###############################################################
#  Generated by:      Cadence Innovus 20.13-s083_1
#  OS:                Linux x86_64(Host ID caddy11)
#  Generated on:      Wed Jun 16 17:47:28 2021
#  Design:            deconv_kernel_estimator_top_level
#  Command:           write_lef_abstract -specifyTopLayer 6 -PGPinLayers {5 6} -noCutObs -stripePin results/deconv_kernel_estimator_top_level.lef
###############################################################

VERSION 5.8 ;

BUSBITCHARS "[]" ;
DIVIDERCHAR "/" ;

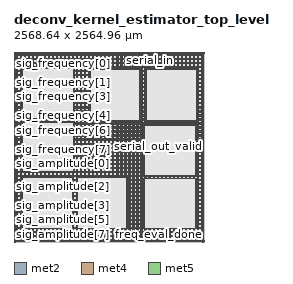
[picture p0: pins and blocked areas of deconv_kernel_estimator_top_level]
MACRO deconv_kernel_estimator_top_level
  CLASS BLOCK ;
  SIZE 2568.640000 BY 2564.960000 ;
  FOREIGN deconv_kernel_estimator_top_level 0.000000 0.000000 ;
  ORIGIN 0 0 ;
  SYMMETRY X Y R90 ;
  PIN clk
    DIRECTION INPUT ;
    USE SIGNAL ;
    ANTENNAPARTIALMETALAREA 5.369 LAYER met2  ;
    ANTENNAPARTIALMETALSIDEAREA 26.684 LAYER met2  ;
    ANTENNAPARTIALCUTAREA 0.04 LAYER via2  ;
    ANTENNAPARTIALMETALAREA 16.5408 LAYER met3  ;
    ANTENNAPARTIALMETALSIDEAREA 88.688 LAYER met3  ;
    ANTENNAMODEL OXIDE1 ;
    ANTENNAGATEAREA 1.152 LAYER met3  ;
    ANTENNAMAXAREACAR 14.9877 LAYER met3  ;
    ANTENNAMAXSIDEAREACAR 78.3273 LAYER met3  ;
    ANTENNAMAXCUTCAR 0.0793403 LAYER via3  ;
    PORT
      LAYER met2 ;
        RECT 1.080000 2564.475000 1.220000 2564.960000 ;
    END
  END clk
  PIN rst_n
    DIRECTION INPUT ;
    USE SIGNAL ;
    ANTENNAPARTIALMETALAREA 18.8185 LAYER met2  ;
    ANTENNAPARTIALMETALSIDEAREA 93.8665 LAYER met2  ;
    ANTENNAMODEL OXIDE1 ;
    ANTENNAGATEAREA 1.33 LAYER met2  ;
    ANTENNAMAXAREACAR 24.5465 LAYER met2  ;
    ANTENNAMAXSIDEAREACAR 121.902 LAYER met2  ;
    ANTENNAMAXCUTCAR 0.0386466 LAYER via2  ;
    PORT
      LAYER met2 ;
        RECT 366.780000 2564.475000 366.920000 2564.960000 ;
    END
  END rst_n
  PIN load_en
    DIRECTION INPUT ;
    USE SIGNAL ;
    ANTENNAPARTIALMETALAREA 125.297 LAYER met2  ;
    ANTENNAPARTIALMETALSIDEAREA 626.206 LAYER met2  ;
    ANTENNAPARTIALCUTAREA 0.04 LAYER via2  ;
    ANTENNAPARTIALMETALAREA 0.255 LAYER met3  ;
    ANTENNAPARTIALMETALSIDEAREA 1.808 LAYER met3  ;
    ANTENNAPARTIALCUTAREA 0.04 LAYER via3  ;
    ANTENNAPARTIALMETALAREA 4.3278 LAYER met4  ;
    ANTENNAPARTIALMETALSIDEAREA 23.552 LAYER met4  ;
    ANTENNAMODEL OXIDE1 ;
    ANTENNAGATEAREA 0.1965 LAYER met4  ;
    ANTENNAMAXAREACAR 29.8453 LAYER met4  ;
    ANTENNAMAXSIDEAREACAR 153.252 LAYER met4  ;
    ANTENNAMAXCUTCAR 0.668702 LAYER via4  ;
    PORT
      LAYER met2 ;
        RECT 733.860000 2564.475000 734.000000 2564.960000 ;
    END
  END load_en
  PIN debug_en
    DIRECTION INPUT ;
    USE SIGNAL ;
    ANTENNAPARTIALMETALAREA 57.8772 LAYER met2  ;
    ANTENNAPARTIALMETALSIDEAREA 289.107 LAYER met2  ;
    ANTENNAPARTIALCUTAREA 0.04 LAYER via2  ;
    ANTENNAPARTIALMETALAREA 11.026 LAYER met3  ;
    ANTENNAPARTIALMETALSIDEAREA 59.272 LAYER met3  ;
    ANTENNAPARTIALCUTAREA 0.04 LAYER via3  ;
    ANTENNAPARTIALMETALAREA 30.9108 LAYER met4  ;
    ANTENNAPARTIALMETALSIDEAREA 165.328 LAYER met4  ;
    ANTENNAMODEL OXIDE1 ;
    ANTENNAGATEAREA 0.441 LAYER met4  ;
    ANTENNAMAXAREACAR 77.8586 LAYER met4  ;
    ANTENNAMAXSIDEAREACAR 407.197 LAYER met4  ;
    ANTENNAMAXCUTCAR 0.589342 LAYER via4  ;
    PORT
      LAYER met2 ;
        RECT 1100.480000 2564.475000 1100.620000 2564.960000 ;
    END
  END debug_en
  PIN serial_in
    DIRECTION INPUT ;
    USE SIGNAL ;
    ANTENNAPARTIALMETALAREA 71.4194 LAYER met2  ;
    ANTENNAPARTIALMETALSIDEAREA 356.818 LAYER met2  ;
    ANTENNAPARTIALCUTAREA 0.04 LAYER via2  ;
    ANTENNAPARTIALMETALAREA 0.2509 LAYER met3  ;
    ANTENNAPARTIALMETALSIDEAREA 1.808 LAYER met3  ;
    ANTENNAPARTIALCUTAREA 0.04 LAYER via3  ;
    ANTENNAPARTIALMETALAREA 3.9618 LAYER met4  ;
    ANTENNAPARTIALMETALSIDEAREA 21.6 LAYER met4  ;
    ANTENNAMODEL OXIDE1 ;
    ANTENNAGATEAREA 0.1965 LAYER met4  ;
    ANTENNAMAXAREACAR 71.0814 LAYER met4  ;
    ANTENNAMAXSIDEAREACAR 363.679 LAYER met4  ;
    ANTENNAMAXCUTCAR 0.668702 LAYER via4  ;
    PORT
      LAYER met2 ;
        RECT 1834.180000 2564.475000 1834.320000 2564.960000 ;
    END
  END serial_in
  PIN sram_select[1]
    DIRECTION INPUT ;
    USE SIGNAL ;
    ANTENNAPARTIALMETALAREA 159.296 LAYER met2  ;
    ANTENNAPARTIALMETALSIDEAREA 796.201 LAYER met2  ;
    ANTENNAPARTIALCUTAREA 0.04 LAYER via2  ;
    ANTENNAPARTIALMETALAREA 0.2509 LAYER met3  ;
    ANTENNAPARTIALMETALSIDEAREA 1.808 LAYER met3  ;
    ANTENNAPARTIALCUTAREA 0.04 LAYER via3  ;
    ANTENNAPARTIALMETALAREA 4.1448 LAYER met4  ;
    ANTENNAPARTIALMETALSIDEAREA 22.576 LAYER met4  ;
    ANTENNAMODEL OXIDE1 ;
    ANTENNAGATEAREA 1.33 LAYER met4  ;
    ANTENNAMAXAREACAR 7.30962 LAYER met4  ;
    ANTENNAMAXSIDEAREACAR 37.5669 LAYER met4  ;
    ANTENNAMAXCUTCAR 0.098797 LAYER via4  ;
    PORT
      LAYER met2 ;
        RECT 2567.420000 2564.475000 2567.560000 2564.960000 ;
    END
  END sram_select[1]
  PIN sram_select[0]
    DIRECTION INPUT ;
    USE SIGNAL ;
    ANTENNAPARTIALMETALAREA 90.3334 LAYER met2  ;
    ANTENNAPARTIALMETALSIDEAREA 451.388 LAYER met2  ;
    ANTENNAPARTIALCUTAREA 0.04 LAYER via2  ;
    ANTENNAPARTIALMETALAREA 0.676 LAYER met3  ;
    ANTENNAPARTIALMETALSIDEAREA 4.072 LAYER met3  ;
    ANTENNAPARTIALCUTAREA 0.04 LAYER via3  ;
    ANTENNAPARTIALMETALAREA 7.9878 LAYER met4  ;
    ANTENNAPARTIALMETALSIDEAREA 43.072 LAYER met4  ;
    ANTENNAMODEL OXIDE1 ;
    ANTENNAGATEAREA 0.665 LAYER met4  ;
    ANTENNAMAXAREACAR 19.8565 LAYER met4  ;
    ANTENNAMAXSIDEAREACAR 101.424 LAYER met4  ;
    ANTENNAMAXCUTCAR 0.197594 LAYER via4  ;
    PORT
      LAYER met2 ;
        RECT 2201.260000 2564.475000 2201.400000 2564.960000 ;
    END
  END sram_select[0]
  PIN frequency_adc_done
    DIRECTION INPUT ;
    USE SIGNAL ;
    ANTENNAPARTIALMETALAREA 162.19 LAYER met2  ;
    ANTENNAPARTIALMETALSIDEAREA 810.673 LAYER met2  ;
    ANTENNAPARTIALCUTAREA 0.04 LAYER via2  ;
    ANTENNAPARTIALMETALAREA 0.2509 LAYER met3  ;
    ANTENNAPARTIALMETALSIDEAREA 1.808 LAYER met3  ;
    ANTENNAPARTIALCUTAREA 0.04 LAYER via3  ;
    ANTENNAPARTIALMETALAREA 4.1448 LAYER met4  ;
    ANTENNAPARTIALMETALSIDEAREA 22.576 LAYER met4  ;
    ANTENNAMODEL OXIDE1 ;
    ANTENNAGATEAREA 0.495 LAYER met4  ;
    ANTENNAMAXAREACAR 17.5144 LAYER met4  ;
    ANTENNAMAXSIDEAREACAR 89.9354 LAYER met4  ;
    ANTENNAMAXCUTCAR 0.265455 LAYER via4  ;
    PORT
      LAYER met2 ;
        RECT 0.000000 2564.720000 0.485000 2564.860000 ;
    END
  END frequency_adc_done
  PIN amplitude_adc_done
    DIRECTION INPUT ;
    USE SIGNAL ;
    ANTENNAPARTIALMETALAREA 26.1573 LAYER met2  ;
    ANTENNAPARTIALMETALSIDEAREA 130.561 LAYER met2  ;
    ANTENNAMODEL OXIDE1 ;
    ANTENNAGATEAREA 0.495 LAYER met2  ;
    ANTENNAMAXAREACAR 60.9542 LAYER met2  ;
    ANTENNAMAXSIDEAREACAR 302.471 LAYER met2  ;
    ANTENNAMAXCUTCAR 0.103838 LAYER via2  ;
    PORT
      LAYER met2 ;
        RECT 0.000000 1206.760000 0.485000 1206.900000 ;
    END
  END amplitude_adc_done
  PIN sig_frequency[7]
    DIRECTION INPUT ;
    USE SIGNAL ;
    ANTENNAPARTIALMETALAREA 0.1351 LAYER met2  ;
    ANTENNAPARTIALMETALSIDEAREA 0.5145 LAYER met2  ;
    ANTENNAPARTIALCUTAREA 0.04 LAYER via2  ;
    ANTENNAPARTIALMETALAREA 26.182 LAYER met3  ;
    ANTENNAPARTIALMETALSIDEAREA 140.104 LAYER met3  ;
    ANTENNAPARTIALCUTAREA 0.04 LAYER via3  ;
    ANTENNAPARTIALMETALAREA 1.45345 LAYER met4  ;
    ANTENNAPARTIALMETALSIDEAREA 4.072 LAYER met4  ;
    ANTENNAPARTIALCUTAREA 0.64 LAYER via4  ;
    ANTENNADIFFAREA 5.2164 LAYER met5  ;
    ANTENNAPARTIALMETALAREA 1190.46 LAYER met5  ;
    ANTENNAPARTIALMETALSIDEAREA 1789.54 LAYER met5  ;
    ANTENNAMODEL OXIDE1 ;
    ANTENNAGATEAREA 5.7114 LAYER met5  ;
    ANTENNAMAXAREACAR 214.365 LAYER met5  ;
    ANTENNAMAXSIDEAREACAR 324.405 LAYER met5  ;
    PORT
      LAYER met2 ;
        RECT 0.000000 1357.720000 0.485000 1357.860000 ;
    END
  END sig_frequency[7]
  PIN sig_frequency[6]
    DIRECTION INPUT ;
    USE SIGNAL ;
    ANTENNAPARTIALMETALAREA 15.2153 LAYER met2  ;
    ANTENNAPARTIALMETALSIDEAREA 75.8905 LAYER met2  ;
    ANTENNAPARTIALCUTAREA 0.04 LAYER via2  ;
    ANTENNAPARTIALMETALAREA 1.4988 LAYER met3  ;
    ANTENNAPARTIALMETALSIDEAREA 8.464 LAYER met3  ;
    ANTENNAMODEL OXIDE1 ;
    ANTENNAGATEAREA 0.495 LAYER met3  ;
    ANTENNAMAXAREACAR 17.4051 LAYER met3  ;
    ANTENNAMAXSIDEAREACAR 85.2636 LAYER met3  ;
    ANTENNAMAXCUTCAR 0.379394 LAYER via3  ;
    PORT
      LAYER met2 ;
        RECT 0.000000 1508.680000 0.485000 1508.820000 ;
    END
  END sig_frequency[6]
  PIN sig_frequency[5]
    DIRECTION INPUT ;
    USE SIGNAL ;
    ANTENNAPARTIALMETALAREA 38.7021 LAYER met2  ;
    ANTENNAPARTIALMETALSIDEAREA 193.232 LAYER met2  ;
    ANTENNAPARTIALCUTAREA 0.04 LAYER via2  ;
    ANTENNAPARTIALMETALAREA 0.4 LAYER met3  ;
    ANTENNAPARTIALMETALSIDEAREA 2.6 LAYER met3  ;
    ANTENNAPARTIALCUTAREA 0.04 LAYER via3  ;
    ANTENNAPARTIALMETALAREA 6.1578 LAYER met4  ;
    ANTENNAPARTIALMETALSIDEAREA 33.312 LAYER met4  ;
    ANTENNAMODEL OXIDE1 ;
    ANTENNAGATEAREA 0.495 LAYER met4  ;
    ANTENNAMAXAREACAR 47.9881 LAYER met4  ;
    ANTENNAMAXSIDEAREACAR 242.73 LAYER met4  ;
    ANTENNAMAXCUTCAR 0.460202 LAYER via4  ;
    PORT
      LAYER met2 ;
        RECT 0.000000 1659.300000 0.485000 1659.440000 ;
    END
  END sig_frequency[5]
  PIN sig_frequency[4]
    DIRECTION INPUT ;
    USE SIGNAL ;
    ANTENNAPARTIALMETALAREA 0.3611 LAYER met2  ;
    ANTENNAPARTIALMETALSIDEAREA 1.6345 LAYER met2  ;
    ANTENNAPARTIALCUTAREA 0.04 LAYER via2  ;
    ANTENNAPARTIALMETALAREA 3.8448 LAYER met3  ;
    ANTENNAPARTIALMETALSIDEAREA 20.976 LAYER met3  ;
    ANTENNAMODEL OXIDE1 ;
    ANTENNAGATEAREA 0.1965 LAYER met3  ;
    ANTENNAMAXAREACAR 22.6534 LAYER met3  ;
    ANTENNAMAXSIDEAREACAR 119.074 LAYER met3  ;
    ANTENNAMAXCUTCAR 0.46514 LAYER via3  ;
    PORT
      LAYER met2 ;
        RECT 0.000000 1810.260000 0.485000 1810.400000 ;
    END
  END sig_frequency[4]
  PIN sig_frequency[3]
    DIRECTION INPUT ;
    USE SIGNAL ;
    ANTENNAPARTIALMETALAREA 3.1835 LAYER met2  ;
    ANTENNAPARTIALMETALSIDEAREA 15.8095 LAYER met2  ;
    ANTENNAMODEL OXIDE1 ;
    ANTENNAGATEAREA 1.33 LAYER met2  ;
    ANTENNAMAXAREACAR 10.612 LAYER met2  ;
    ANTENNAMAXSIDEAREACAR 52.3173 LAYER met2  ;
    ANTENNAMAXCUTCAR 0.0386466 LAYER via2  ;
    PORT
      LAYER met2 ;
        RECT 0.000000 1961.220000 0.485000 1961.360000 ;
    END
  END sig_frequency[3]
  PIN sig_frequency[2]
    DIRECTION INPUT ;
    USE SIGNAL ;
    ANTENNAPARTIALMETALAREA 4.4302 LAYER met2  ;
    ANTENNAPARTIALMETALSIDEAREA 22.043 LAYER met2  ;
    ANTENNAMODEL OXIDE1 ;
    ANTENNAGATEAREA 1.33 LAYER met2  ;
    ANTENNAMAXAREACAR 9.84196 LAYER met2  ;
    ANTENNAMAXSIDEAREACAR 48.4673 LAYER met2  ;
    ANTENNAMAXCUTCAR 0.0386466 LAYER via2  ;
    PORT
      LAYER met2 ;
        RECT 0.000000 2111.840000 0.485000 2111.980000 ;
    END
  END sig_frequency[2]
  PIN sig_frequency[1]
    DIRECTION INPUT ;
    USE SIGNAL ;
    ANTENNAPARTIALMETALAREA 110.31 LAYER met2  ;
    ANTENNAPARTIALMETALSIDEAREA 551.271 LAYER met2  ;
    ANTENNAPARTIALCUTAREA 0.04 LAYER via2  ;
    ANTENNAPARTIALMETALAREA 0.255 LAYER met3  ;
    ANTENNAPARTIALMETALSIDEAREA 1.808 LAYER met3  ;
    ANTENNAPARTIALCUTAREA 0.04 LAYER via3  ;
    ANTENNAPARTIALMETALAREA 4.1448 LAYER met4  ;
    ANTENNAPARTIALMETALSIDEAREA 22.576 LAYER met4  ;
    ANTENNAMODEL OXIDE1 ;
    ANTENNAGATEAREA 1.33 LAYER met4  ;
    ANTENNAMAXAREACAR 6.64639 LAYER met4  ;
    ANTENNAMAXSIDEAREACAR 34.2353 LAYER met4  ;
    ANTENNAMAXCUTCAR 0.098797 LAYER via4  ;
    PORT
      LAYER met2 ;
        RECT 0.000000 2262.800000 0.485000 2262.940000 ;
    END
  END sig_frequency[1]
  PIN sig_frequency[0]
    DIRECTION INPUT ;
    USE SIGNAL ;
    ANTENNAPARTIALMETALAREA 47.4157 LAYER met2  ;
    ANTENNAPARTIALMETALSIDEAREA 236.799 LAYER met2  ;
    ANTENNAPARTIALCUTAREA 0.04 LAYER via2  ;
    ANTENNAPARTIALMETALAREA 0.255 LAYER met3  ;
    ANTENNAPARTIALMETALSIDEAREA 1.808 LAYER met3  ;
    ANTENNAPARTIALCUTAREA 0.04 LAYER via3  ;
    ANTENNAPARTIALMETALAREA 8.1708 LAYER met4  ;
    ANTENNAPARTIALMETALSIDEAREA 44.048 LAYER met4  ;
    ANTENNAMODEL OXIDE1 ;
    ANTENNAGATEAREA 0.1965 LAYER met4  ;
    ANTENNAMAXAREACAR 126.457 LAYER met4  ;
    ANTENNAMAXSIDEAREACAR 646.204 LAYER met4  ;
    ANTENNAMAXCUTCAR 0.668702 LAYER via4  ;
    PORT
      LAYER met2 ;
        RECT 0.000000 2413.760000 0.485000 2413.900000 ;
    END
  END sig_frequency[0]
  PIN sig_amplitude[7]
    DIRECTION INPUT ;
    USE SIGNAL ;
    ANTENNAPARTIALMETALAREA 179.86 LAYER met2  ;
    ANTENNAPARTIALMETALSIDEAREA 899.021 LAYER met2  ;
    ANTENNAPARTIALCUTAREA 0.04 LAYER via2  ;
    ANTENNAPARTIALMETALAREA 0.2509 LAYER met3  ;
    ANTENNAPARTIALMETALSIDEAREA 1.808 LAYER met3  ;
    ANTENNAPARTIALCUTAREA 0.04 LAYER via3  ;
    ANTENNAPARTIALMETALAREA 6.1578 LAYER met4  ;
    ANTENNAPARTIALMETALSIDEAREA 33.312 LAYER met4  ;
    ANTENNAMODEL OXIDE1 ;
    ANTENNAGATEAREA 0.665 LAYER met4  ;
    ANTENNAMAXAREACAR 15.3956 LAYER met4  ;
    ANTENNAMAXSIDEAREACAR 79.2767 LAYER met4  ;
    ANTENNAMAXCUTCAR 0.197594 LAYER via4  ;
    PORT
      LAYER met2 ;
        RECT 0.000000 0.100000 0.485000 0.240000 ;
    END
  END sig_amplitude[7]
  PIN sig_amplitude[6]
    DIRECTION INPUT ;
    USE SIGNAL ;
    ANTENNAPARTIALMETALAREA 16.071 LAYER met2  ;
    ANTENNAPARTIALMETALSIDEAREA 80.129 LAYER met2  ;
    ANTENNAMODEL OXIDE1 ;
    ANTENNAGATEAREA 0.665 LAYER met2  ;
    ANTENNAMAXAREACAR 27.7171 LAYER met2  ;
    ANTENNAMAXSIDEAREACAR 136.175 LAYER met2  ;
    ANTENNAMAXCUTCAR 0.0772932 LAYER via2  ;
    PORT
      LAYER met2 ;
        RECT 0.000000 150.720000 0.485000 150.860000 ;
    END
  END sig_amplitude[6]
  PIN sig_amplitude[5]
    DIRECTION INPUT ;
    USE SIGNAL ;
    ANTENNAPARTIALMETALAREA 141.558 LAYER met2  ;
    ANTENNAPARTIALMETALSIDEAREA 707.511 LAYER met2  ;
    ANTENNAPARTIALCUTAREA 0.04 LAYER via2  ;
    ANTENNAPARTIALMETALAREA 0.2509 LAYER met3  ;
    ANTENNAPARTIALMETALSIDEAREA 1.808 LAYER met3  ;
    ANTENNAPARTIALCUTAREA 0.04 LAYER via3  ;
    ANTENNAPARTIALMETALAREA 3.9618 LAYER met4  ;
    ANTENNAPARTIALMETALSIDEAREA 21.6 LAYER met4  ;
    ANTENNAMODEL OXIDE1 ;
    ANTENNAGATEAREA 0.665 LAYER met4  ;
    ANTENNAMAXAREACAR 12.5489 LAYER met4  ;
    ANTENNAMAXSIDEAREACAR 62.8286 LAYER met4  ;
    ANTENNAMAXCUTCAR 0.197594 LAYER via4  ;
    PORT
      LAYER met2 ;
        RECT 0.000000 301.680000 0.485000 301.820000 ;
    END
  END sig_amplitude[5]
  PIN sig_amplitude[4]
    DIRECTION INPUT ;
    USE SIGNAL ;
    ANTENNAPARTIALMETALAREA 114.621 LAYER met2  ;
    ANTENNAPARTIALMETALSIDEAREA 572.828 LAYER met2  ;
    ANTENNAPARTIALCUTAREA 0.04 LAYER via2  ;
    ANTENNAPARTIALMETALAREA 0.255 LAYER met3  ;
    ANTENNAPARTIALMETALSIDEAREA 1.808 LAYER met3  ;
    ANTENNAPARTIALCUTAREA 0.04 LAYER via3  ;
    ANTENNAPARTIALMETALAREA 3.9618 LAYER met4  ;
    ANTENNAPARTIALMETALSIDEAREA 21.6 LAYER met4  ;
    ANTENNAMODEL OXIDE1 ;
    ANTENNAGATEAREA 1.33 LAYER met4  ;
    ANTENNAMAXAREACAR 6.18774 LAYER met4  ;
    ANTENNAMAXSIDEAREACAR 31.8962 LAYER met4  ;
    ANTENNAMAXCUTCAR 0.098797 LAYER via4  ;
    PORT
      LAYER met2 ;
        RECT 0.000000 452.640000 0.485000 452.780000 ;
    END
  END sig_amplitude[4]
  PIN sig_amplitude[3]
    DIRECTION INPUT ;
    USE SIGNAL ;
    ANTENNAPARTIALMETALAREA 98.7564 LAYER met2  ;
    ANTENNAPARTIALMETALSIDEAREA 493.556 LAYER met2  ;
    ANTENNAMODEL OXIDE1 ;
    ANTENNAGATEAREA 1.33 LAYER met2  ;
    ANTENNAMAXAREACAR 77.2165 LAYER met2  ;
    ANTENNAMAXSIDEAREACAR 385.251 LAYER met2  ;
    ANTENNAMAXCUTCAR 0.0386466 LAYER via2  ;
    PORT
      LAYER met2 ;
        RECT 0.000000 603.260000 0.485000 603.400000 ;
    END
  END sig_amplitude[3]
  PIN sig_amplitude[2]
    DIRECTION INPUT ;
    USE SIGNAL ;
    ANTENNAPARTIALMETALAREA 79.7598 LAYER met2  ;
    ANTENNAPARTIALMETALSIDEAREA 398.573 LAYER met2  ;
    ANTENNAMODEL OXIDE1 ;
    ANTENNAGATEAREA 1.33 LAYER met2  ;
    ANTENNAMAXAREACAR 62.7071 LAYER met2  ;
    ANTENNAMAXSIDEAREACAR 312.704 LAYER met2  ;
    ANTENNAMAXCUTCAR 0.0386466 LAYER via2  ;
    PORT
      LAYER met2 ;
        RECT 0.000000 754.220000 0.485000 754.360000 ;
    END
  END sig_amplitude[2]
  PIN sig_amplitude[1]
    DIRECTION INPUT ;
    USE SIGNAL ;
    ANTENNAPARTIALMETALAREA 16.5371 LAYER met2  ;
    ANTENNAPARTIALMETALSIDEAREA 82.2885 LAYER met2  ;
    ANTENNAPARTIALCUTAREA 0.04 LAYER via2  ;
    ANTENNAPARTIALMETALAREA 15.4117 LAYER met3  ;
    ANTENNAPARTIALMETALSIDEAREA 83.136 LAYER met3  ;
    ANTENNAPARTIALCUTAREA 0.04 LAYER via3  ;
    ANTENNAPARTIALMETALAREA 3.9618 LAYER met4  ;
    ANTENNAPARTIALMETALSIDEAREA 21.6 LAYER met4  ;
    ANTENNAMODEL OXIDE1 ;
    ANTENNAGATEAREA 0.2475 LAYER met4  ;
    ANTENNAMAXAREACAR 21.0972 LAYER met4  ;
    ANTENNAMAXSIDEAREACAR 112.317 LAYER met4  ;
    ANTENNAMAXCUTCAR 0.530909 LAYER via4  ;
    PORT
      LAYER met2 ;
        RECT 0.000000 905.180000 0.485000 905.320000 ;
    END
  END sig_amplitude[1]
  PIN sig_amplitude[0]
    DIRECTION INPUT ;
    USE SIGNAL ;
    ANTENNAPARTIALMETALAREA 33.3683 LAYER met2  ;
    ANTENNAPARTIALMETALSIDEAREA 166.68 LAYER met2  ;
    ANTENNAPARTIALCUTAREA 0.04 LAYER via2  ;
    ANTENNAPARTIALMETALAREA 26.068 LAYER met3  ;
    ANTENNAPARTIALMETALSIDEAREA 139.496 LAYER met3  ;
    ANTENNAPARTIALCUTAREA 0.04 LAYER via3  ;
    ANTENNAPARTIALMETALAREA 2.3728 LAYER met4  ;
    ANTENNAPARTIALMETALSIDEAREA 9 LAYER met4  ;
    ANTENNAPARTIALCUTAREA 0.64 LAYER via4  ;
    ANTENNADIFFAREA 4.347 LAYER met5  ;
    ANTENNAPARTIALMETALAREA 1262.9 LAYER met5  ;
    ANTENNAPARTIALMETALSIDEAREA 1898.18 LAYER met5  ;
    ANTENNAMODEL OXIDE1 ;
    ANTENNAGATEAREA 4.5945 LAYER met5  ;
    ANTENNAMAXAREACAR 280.672 LAYER met5  ;
    ANTENNAMAXSIDEAREACAR 423.898 LAYER met5  ;
    PORT
      LAYER met2 ;
        RECT 0.000000 1055.800000 0.485000 1055.940000 ;
    END
  END sig_amplitude[0]
  PIN adc_bypass_en
    DIRECTION INPUT ;
    USE SIGNAL ;
    ANTENNAPARTIALMETALAREA 121.587 LAYER met2  ;
    ANTENNAPARTIALMETALSIDEAREA 607.656 LAYER met2  ;
    ANTENNAPARTIALCUTAREA 0.04 LAYER via2  ;
    ANTENNAPARTIALMETALAREA 0.2509 LAYER met3  ;
    ANTENNAPARTIALMETALSIDEAREA 1.808 LAYER met3  ;
    ANTENNAPARTIALCUTAREA 0.04 LAYER via3  ;
    ANTENNAPARTIALMETALAREA 4.1448 LAYER met4  ;
    ANTENNAPARTIALMETALSIDEAREA 22.576 LAYER met4  ;
    ANTENNAMODEL OXIDE1 ;
    ANTENNAGATEAREA 0.665 LAYER met4  ;
    ANTENNAMAXAREACAR 9.12429 LAYER met4  ;
    ANTENNAMAXSIDEAREACAR 46.9113 LAYER met4  ;
    ANTENNAMAXCUTCAR 0.197594 LAYER via4  ;
    PORT
      LAYER met2 ;
        RECT 1467.560000 2564.475000 1467.700000 2564.960000 ;
    END
  END adc_bypass_en
  PIN serial_out
    DIRECTION OUTPUT ;
    USE SIGNAL ;
    ANTENNADIFFAREA 0.3406 LAYER met2  ;
    ANTENNAPARTIALMETALAREA 4.6659 LAYER met2  ;
    ANTENNAPARTIALMETALSIDEAREA 23.1035 LAYER met2  ;
    PORT
      LAYER met2 ;
        RECT 2568.155000 2564.720000 2568.640000 2564.860000 ;
    END
  END serial_out
  PIN serial_out_valid
    DIRECTION OUTPUT ;
    USE SIGNAL ;
    ANTENNADIFFAREA 0.429 LAYER met2  ;
    ANTENNAPARTIALMETALAREA 1.5679 LAYER met2  ;
    ANTENNAPARTIALMETALSIDEAREA 7.7315 LAYER met2  ;
    PORT
      LAYER met2 ;
        RECT 2568.155000 1282.580000 2568.640000 1282.720000 ;
    END
  END serial_out_valid
  PIN freq_eval_done
    DIRECTION OUTPUT ;
    USE SIGNAL ;
    ANTENNADIFFAREA 0.714 LAYER met2  ;
    ANTENNAPARTIALMETALAREA 183.631 LAYER met2  ;
    ANTENNAPARTIALMETALSIDEAREA 917.931 LAYER met2  ;
    PORT
      LAYER met2 ;
        RECT 2568.155000 0.100000 2568.640000 0.240000 ;
    END
  END freq_eval_done
  PIN VSS
    DIRECTION INOUT ;
    USE GROUND ;
    PORT
      LAYER met4 ;
        RECT 2555.980000 2556.800000 2564.140000 2564.960000 ;
    END
    PORT
      LAYER met4 ;
        RECT 2555.980000 0.000000 2564.140000 8.160000 ;
    END
    PORT
      LAYER met4 ;
        RECT 4.500000 2556.800000 12.660000 2564.960000 ;
    END
    PORT
      LAYER met4 ;
        RECT 4.500000 0.000000 12.660000 8.160000 ;
    END
    PORT
      LAYER met5 ;
        RECT 2560.480000 2552.720000 2568.640000 2560.880000 ;
    END
    PORT
      LAYER met5 ;
        RECT 0.000000 2552.720000 8.160000 2560.880000 ;
    END
    PORT
      LAYER met5 ;
        RECT 2560.480000 4.080000 2568.640000 12.240000 ;
    END
    PORT
      LAYER met5 ;
        RECT 0.000000 4.080000 8.160000 12.240000 ;
    END

# P/G power stripe data as pin
    PORT
      LAYER met4 ;
        RECT 109.300000 943.600000 111.100000 1624.100000 ;
        RECT 81.600000 4.080000 84.960000 2560.880000 ;
        RECT 27.200000 4.080000 30.560000 2560.880000 ;
        RECT 4.500000 0.000000 12.660000 2564.960000 ;
        RECT 897.600000 880.000000 900.960000 2560.880000 ;
        RECT 952.000000 880.000000 955.360000 2560.880000 ;
        RECT 843.200000 4.080000 846.560000 2560.880000 ;
        RECT 811.800000 943.600000 813.600000 1624.100000 ;
        RECT 1006.400000 880.000000 1009.760000 2560.880000 ;
        RECT 1115.200000 880.000000 1118.560000 1633.300000 ;
        RECT 1060.800000 880.000000 1064.160000 1633.300000 ;
        RECT 1278.400000 880.000000 1281.760000 1633.300000 ;
        RECT 1224.000000 880.000000 1227.360000 1633.300000 ;
        RECT 1169.600000 880.000000 1172.960000 1633.300000 ;
        RECT 1604.800000 4.080000 1608.160000 1633.300000 ;
        RECT 1332.800000 880.000000 1336.160000 1633.300000 ;
        RECT 1387.200000 880.000000 1390.560000 1633.300000 ;
        RECT 1441.600000 880.000000 1444.960000 1633.300000 ;
        RECT 1496.000000 880.000000 1499.360000 1633.300000 ;
        RECT 1550.400000 4.080000 1553.760000 1633.300000 ;
        RECT 1659.200000 4.080000 1662.560000 1633.300000 ;
        RECT 1713.600000 4.080000 1716.960000 2560.880000 ;
        RECT 1753.300000 897.500000 1755.100000 1578.000000 ;
        RECT 2455.800000 897.500000 2457.600000 1578.000000 ;
        RECT 2529.600000 4.080000 2532.960000 2560.880000 ;
        RECT 2475.200000 4.080000 2478.560000 2560.880000 ;
        RECT 2555.980000 0.000000 2564.140000 2564.960000 ;
        RECT 849.300000 177.500000 851.100000 881.800000 ;
        RECT 788.000000 177.500000 789.800000 881.800000 ;
        RECT 109.300000 177.500000 111.100000 881.800000 ;
        RECT 136.000000 4.080000 139.360000 179.300000 ;
        RECT 190.400000 4.080000 193.760000 179.300000 ;
        RECT 244.800000 4.080000 248.160000 179.300000 ;
        RECT 299.200000 4.080000 302.560000 179.300000 ;
        RECT 353.600000 4.080000 356.960000 179.300000 ;
        RECT 408.000000 4.080000 411.360000 179.300000 ;
        RECT 462.400000 4.080000 465.760000 179.300000 ;
        RECT 516.800000 4.080000 520.160000 179.300000 ;
        RECT 571.200000 4.080000 574.560000 179.300000 ;
        RECT 625.600000 4.080000 628.960000 179.300000 ;
        RECT 952.000000 4.080000 955.360000 179.300000 ;
        RECT 897.600000 4.080000 900.960000 179.300000 ;
        RECT 788.800000 4.080000 792.160000 179.300000 ;
        RECT 680.000000 4.080000 683.360000 179.300000 ;
        RECT 734.400000 4.080000 737.760000 179.300000 ;
        RECT 1278.400000 4.080000 1281.760000 179.300000 ;
        RECT 1224.000000 4.080000 1227.360000 179.300000 ;
        RECT 1169.600000 4.080000 1172.960000 179.300000 ;
        RECT 1115.200000 4.080000 1118.560000 179.300000 ;
        RECT 1060.800000 4.080000 1064.160000 179.300000 ;
        RECT 1006.400000 4.080000 1009.760000 179.300000 ;
        RECT 136.000000 880.000000 139.360000 945.400000 ;
        RECT 190.400000 880.000000 193.760000 945.400000 ;
        RECT 244.800000 880.000000 248.160000 945.400000 ;
        RECT 299.200000 880.000000 302.560000 945.400000 ;
        RECT 353.600000 880.000000 356.960000 945.400000 ;
        RECT 408.000000 880.000000 411.360000 945.400000 ;
        RECT 462.400000 880.000000 465.760000 945.400000 ;
        RECT 516.800000 880.000000 520.160000 945.400000 ;
        RECT 571.200000 880.000000 574.560000 945.400000 ;
        RECT 625.600000 880.000000 628.960000 945.400000 ;
        RECT 680.000000 880.000000 683.360000 945.400000 ;
        RECT 734.400000 880.000000 737.760000 945.400000 ;
        RECT 788.800000 880.000000 792.160000 945.400000 ;
        RECT 1528.000000 177.500000 1529.800000 881.800000 ;
        RECT 2455.800000 177.500000 2457.600000 858.000000 ;
        RECT 1753.300000 177.500000 1755.100000 858.000000 ;
        RECT 1332.800000 4.080000 1336.160000 179.300000 ;
        RECT 1387.200000 4.080000 1390.560000 179.300000 ;
        RECT 1441.600000 4.080000 1444.960000 179.300000 ;
        RECT 1496.000000 4.080000 1499.360000 179.300000 ;
        RECT 1768.000000 4.080000 1771.360000 179.300000 ;
        RECT 1822.400000 4.080000 1825.760000 179.300000 ;
        RECT 1876.800000 4.080000 1880.160000 179.300000 ;
        RECT 2203.200000 4.080000 2206.560000 179.300000 ;
        RECT 1931.200000 4.080000 1934.560000 179.300000 ;
        RECT 1985.600000 4.080000 1988.960000 179.300000 ;
        RECT 2040.000000 4.080000 2043.360000 179.300000 ;
        RECT 2094.400000 4.080000 2097.760000 179.300000 ;
        RECT 2148.800000 4.080000 2152.160000 179.300000 ;
        RECT 2420.800000 4.080000 2424.160000 179.300000 ;
        RECT 2366.400000 4.080000 2369.760000 179.300000 ;
        RECT 2312.000000 4.080000 2315.360000 179.300000 ;
        RECT 2257.600000 4.080000 2260.960000 179.300000 ;
        RECT 2443.900000 195.330000 2445.640000 197.630000 ;
        RECT 2443.900000 190.330000 2445.640000 196.480000 ;
        RECT 1768.000000 856.200000 1771.360000 899.300000 ;
        RECT 1822.400000 856.200000 1825.760000 899.300000 ;
        RECT 1876.800000 856.200000 1880.160000 899.300000 ;
        RECT 1931.200000 856.200000 1934.560000 899.300000 ;
        RECT 1985.600000 856.200000 1988.960000 899.300000 ;
        RECT 2040.000000 856.200000 2043.360000 899.300000 ;
        RECT 2094.400000 856.200000 2097.760000 899.300000 ;
        RECT 2148.800000 856.200000 2152.160000 899.300000 ;
        RECT 2203.200000 856.200000 2206.560000 899.300000 ;
        RECT 2257.600000 856.200000 2260.960000 899.300000 ;
        RECT 2312.000000 856.200000 2315.360000 899.300000 ;
        RECT 2366.400000 856.200000 2369.760000 899.300000 ;
        RECT 2420.800000 856.200000 2424.160000 899.300000 ;
        RECT 1024.300000 1631.500000 1026.100000 2335.800000 ;
        RECT 811.800000 1663.600000 813.600000 2344.100000 ;
        RECT 109.300000 1663.600000 111.100000 2344.100000 ;
        RECT 136.000000 1622.300000 139.360000 1665.400000 ;
        RECT 190.400000 1622.300000 193.760000 1665.400000 ;
        RECT 244.800000 1622.300000 248.160000 1665.400000 ;
        RECT 299.200000 1622.300000 302.560000 1665.400000 ;
        RECT 353.600000 1622.300000 356.960000 1665.400000 ;
        RECT 408.000000 1622.300000 411.360000 1665.400000 ;
        RECT 462.400000 1622.300000 465.760000 1665.400000 ;
        RECT 516.800000 1622.300000 520.160000 1665.400000 ;
        RECT 571.200000 1622.300000 574.560000 1665.400000 ;
        RECT 625.600000 1622.300000 628.960000 1665.400000 ;
        RECT 680.000000 1622.300000 683.360000 1665.400000 ;
        RECT 734.400000 1622.300000 737.760000 1665.400000 ;
        RECT 788.800000 1622.300000 792.160000 1665.400000 ;
        RECT 136.000000 2342.300000 139.360000 2560.880000 ;
        RECT 190.400000 2342.300000 193.760000 2560.880000 ;
        RECT 244.800000 2342.300000 248.160000 2560.880000 ;
        RECT 299.200000 2342.300000 302.560000 2560.880000 ;
        RECT 353.600000 2342.300000 356.960000 2560.880000 ;
        RECT 408.000000 2342.300000 411.360000 2560.880000 ;
        RECT 462.400000 2342.300000 465.760000 2560.880000 ;
        RECT 516.800000 2342.300000 520.160000 2560.880000 ;
        RECT 571.200000 2342.300000 574.560000 2560.880000 ;
        RECT 625.600000 2342.300000 628.960000 2560.880000 ;
        RECT 680.000000 2342.300000 683.360000 2560.880000 ;
        RECT 734.400000 2342.300000 737.760000 2560.880000 ;
        RECT 788.800000 2342.300000 792.160000 2560.880000 ;
        RECT 1278.400000 2334.000000 1281.760000 2560.880000 ;
        RECT 1224.000000 2334.000000 1227.360000 2560.880000 ;
        RECT 1060.800000 2334.000000 1064.160000 2560.880000 ;
        RECT 1115.200000 2334.000000 1118.560000 2560.880000 ;
        RECT 1169.600000 2334.000000 1172.960000 2560.880000 ;
        RECT 2463.000000 1631.500000 2464.800000 2335.800000 ;
        RECT 1784.300000 1631.500000 1786.100000 2335.800000 ;
        RECT 1703.000000 1631.500000 1704.800000 2335.800000 ;
        RECT 1768.000000 1576.200000 1771.360000 2560.880000 ;
        RECT 1876.800000 1576.200000 1880.160000 1633.300000 ;
        RECT 1822.400000 1576.200000 1825.760000 1633.300000 ;
        RECT 1931.200000 1576.200000 1934.560000 1633.300000 ;
        RECT 1985.600000 1576.200000 1988.960000 1633.300000 ;
        RECT 2040.000000 1576.200000 2043.360000 1633.300000 ;
        RECT 2094.400000 1576.200000 2097.760000 1633.300000 ;
        RECT 2148.800000 1576.200000 2152.160000 1633.300000 ;
        RECT 2203.200000 1576.200000 2206.560000 1633.300000 ;
        RECT 2420.800000 1576.200000 2424.160000 1633.300000 ;
        RECT 2366.400000 1576.200000 2369.760000 1633.300000 ;
        RECT 2312.000000 1576.200000 2315.360000 1633.300000 ;
        RECT 2257.600000 1576.200000 2260.960000 1633.300000 ;
        RECT 1604.800000 2334.000000 1608.160000 2560.880000 ;
        RECT 1332.800000 2334.000000 1336.160000 2560.880000 ;
        RECT 1387.200000 2334.000000 1390.560000 2560.880000 ;
        RECT 1441.600000 2334.000000 1444.960000 2560.880000 ;
        RECT 1496.000000 2334.000000 1499.360000 2560.880000 ;
        RECT 1550.400000 2334.000000 1553.760000 2560.880000 ;
        RECT 1659.200000 2334.000000 1662.560000 2560.880000 ;
        RECT 1822.400000 2334.000000 1825.760000 2560.880000 ;
        RECT 1876.800000 2334.000000 1880.160000 2560.880000 ;
        RECT 1931.200000 2334.000000 1934.560000 2560.880000 ;
        RECT 1985.600000 2334.000000 1988.960000 2560.880000 ;
        RECT 2040.000000 2334.000000 2043.360000 2560.880000 ;
        RECT 2094.400000 2334.000000 2097.760000 2560.880000 ;
        RECT 2148.800000 2334.000000 2152.160000 2560.880000 ;
        RECT 2203.200000 2334.000000 2206.560000 2560.880000 ;
        RECT 2420.800000 2334.000000 2424.160000 2560.880000 ;
        RECT 2366.400000 2334.000000 2369.760000 2560.880000 ;
        RECT 2312.000000 2334.000000 2315.360000 2560.880000 ;
        RECT 2257.600000 2334.000000 2260.960000 2560.880000 ;
        RECT 109.300000 176.800000 111.100000 180.160000 ;
        RECT 788.000000 177.500000 792.160000 179.300000 ;
        RECT 849.300000 176.800000 851.100000 180.160000 ;
        RECT 788.000000 880.000000 792.160000 881.800000 ;
        RECT 776.100000 868.100000 777.840000 869.840000 ;
        RECT 861.260000 868.100000 863.000000 869.840000 ;
        RECT 1528.000000 176.800000 1529.800000 180.160000 ;
        RECT 1753.300000 176.800000 1755.100000 180.160000 ;
        RECT 2455.800000 176.800000 2457.600000 180.160000 ;
        RECT 2443.900000 909.460000 2445.640000 911.200000 ;
        RECT 799.900000 1610.400000 801.640000 1612.140000 ;
        RECT 121.260000 2330.400000 123.000000 2332.140000 ;
        RECT 1691.100000 2322.100000 1692.840000 2323.840000 ;
        RECT 2451.100000 2322.100000 2452.840000 2323.840000 ;
      LAYER met5 ;
        RECT 4.500000 68.000000 2564.140000 71.360000 ;
        RECT 0.000000 4.080000 2568.640000 12.240000 ;
        RECT 4.500000 122.400000 2564.140000 125.760000 ;
        RECT 849.300000 177.500000 1529.800000 179.300000 ;
        RECT 849.300000 880.000000 1529.800000 881.800000 ;
        RECT 4.500000 884.000000 2564.140000 887.360000 ;
        RECT 4.500000 938.400000 1755.100000 941.760000 ;
        RECT 811.800000 992.800000 1755.100000 996.160000 ;
        RECT 811.800000 1047.200000 1755.100000 1050.560000 ;
        RECT 811.800000 1101.600000 1755.100000 1104.960000 ;
        RECT 811.800000 1156.000000 1755.100000 1159.360000 ;
        RECT 811.800000 1210.400000 1755.100000 1213.760000 ;
        RECT 811.800000 1264.800000 1755.100000 1268.160000 ;
        RECT 109.300000 177.500000 789.800000 179.300000 ;
        RECT 4.500000 231.200000 111.100000 234.560000 ;
        RECT 4.500000 176.800000 111.100000 180.160000 ;
        RECT 4.500000 285.600000 111.100000 288.960000 ;
        RECT 4.500000 340.000000 111.100000 343.360000 ;
        RECT 4.500000 394.400000 111.100000 397.760000 ;
        RECT 4.500000 448.800000 111.100000 452.160000 ;
        RECT 4.500000 557.600000 111.100000 560.960000 ;
        RECT 4.500000 503.200000 111.100000 506.560000 ;
        RECT 4.500000 612.000000 111.100000 615.360000 ;
        RECT 788.000000 176.800000 851.100000 180.160000 ;
        RECT 788.000000 231.200000 851.100000 234.560000 ;
        RECT 788.000000 285.600000 851.100000 288.960000 ;
        RECT 788.000000 340.000000 851.100000 343.360000 ;
        RECT 788.000000 394.400000 851.100000 397.760000 ;
        RECT 788.000000 448.800000 851.100000 452.160000 ;
        RECT 788.000000 557.600000 851.100000 560.960000 ;
        RECT 788.000000 503.200000 851.100000 506.560000 ;
        RECT 788.000000 612.000000 851.100000 615.360000 ;
        RECT 109.300000 880.000000 789.800000 881.800000 ;
        RECT 109.300000 943.600000 813.600000 945.400000 ;
        RECT 4.500000 666.400000 111.100000 669.760000 ;
        RECT 4.500000 720.800000 111.100000 724.160000 ;
        RECT 4.500000 775.200000 111.100000 778.560000 ;
        RECT 4.500000 829.600000 111.100000 832.960000 ;
        RECT 4.500000 992.800000 111.100000 996.160000 ;
        RECT 4.500000 1047.200000 111.100000 1050.560000 ;
        RECT 4.500000 1101.600000 111.100000 1104.960000 ;
        RECT 4.500000 1156.000000 111.100000 1159.360000 ;
        RECT 4.500000 1210.400000 111.100000 1213.760000 ;
        RECT 4.500000 1264.800000 111.100000 1268.160000 ;
        RECT 788.000000 666.400000 851.100000 669.760000 ;
        RECT 788.000000 720.800000 851.100000 724.160000 ;
        RECT 788.000000 775.200000 851.100000 778.560000 ;
        RECT 788.000000 829.600000 851.100000 832.960000 ;
        RECT 776.970000 868.100000 789.800000 869.840000 ;
        RECT 849.300000 868.100000 862.130000 869.840000 ;
        RECT 1753.300000 177.500000 2457.600000 179.300000 ;
        RECT 1528.000000 176.800000 1755.100000 180.160000 ;
        RECT 1528.000000 231.200000 1755.100000 234.560000 ;
        RECT 1528.000000 285.600000 1755.100000 288.960000 ;
        RECT 1528.000000 340.000000 1755.100000 343.360000 ;
        RECT 1528.000000 394.400000 1755.100000 397.760000 ;
        RECT 1528.000000 448.800000 1755.100000 452.160000 ;
        RECT 1528.000000 557.600000 1755.100000 560.960000 ;
        RECT 1528.000000 503.200000 1755.100000 506.560000 ;
        RECT 1528.000000 612.000000 1755.100000 615.360000 ;
        RECT 2455.800000 176.800000 2564.140000 180.160000 ;
        RECT 2455.800000 231.200000 2564.140000 234.560000 ;
        RECT 2444.770000 195.610000 2457.600000 197.350000 ;
        RECT 2455.800000 285.600000 2564.140000 288.960000 ;
        RECT 2455.800000 340.000000 2564.140000 343.360000 ;
        RECT 2455.800000 394.400000 2564.140000 397.760000 ;
        RECT 2455.800000 448.800000 2564.140000 452.160000 ;
        RECT 2455.800000 557.600000 2564.140000 560.960000 ;
        RECT 2455.800000 503.200000 2564.140000 506.560000 ;
        RECT 2455.800000 612.000000 2564.140000 615.360000 ;
        RECT 1753.300000 897.500000 2457.600000 899.300000 ;
        RECT 1753.300000 856.200000 2457.600000 858.000000 ;
        RECT 1528.000000 666.400000 1755.100000 669.760000 ;
        RECT 1528.000000 720.800000 1755.100000 724.160000 ;
        RECT 1528.000000 775.200000 1755.100000 778.560000 ;
        RECT 1528.000000 829.600000 1755.100000 832.960000 ;
        RECT 2455.800000 666.400000 2564.140000 669.760000 ;
        RECT 2455.800000 720.800000 2564.140000 724.160000 ;
        RECT 2455.800000 775.200000 2564.140000 778.560000 ;
        RECT 2455.800000 829.600000 2564.140000 832.960000 ;
        RECT 2455.800000 938.400000 2564.140000 941.760000 ;
        RECT 2444.570000 909.460000 2457.600000 911.200000 ;
        RECT 2455.800000 992.800000 2564.140000 996.160000 ;
        RECT 2455.800000 1047.200000 2564.140000 1050.560000 ;
        RECT 2455.800000 1101.600000 2564.140000 1104.960000 ;
        RECT 2455.800000 1156.000000 2564.140000 1159.360000 ;
        RECT 2455.800000 1210.400000 2564.140000 1213.760000 ;
        RECT 2455.800000 1264.800000 2564.140000 1268.160000 ;
        RECT 811.800000 1319.200000 1755.100000 1322.560000 ;
        RECT 811.800000 1373.600000 1755.100000 1376.960000 ;
        RECT 811.800000 1428.000000 1755.100000 1431.360000 ;
        RECT 811.800000 1482.400000 1755.100000 1485.760000 ;
        RECT 811.800000 1536.800000 1755.100000 1540.160000 ;
        RECT 811.800000 1591.200000 2564.140000 1594.560000 ;
        RECT 1024.300000 1631.500000 1704.800000 1633.300000 ;
        RECT 1024.300000 2334.000000 1704.800000 2335.800000 ;
        RECT 4.500000 2352.800000 2564.140000 2356.160000 ;
        RECT 4.500000 2407.200000 2564.140000 2410.560000 ;
        RECT 4.500000 2461.600000 2564.140000 2464.960000 ;
        RECT 4.500000 2516.000000 2564.140000 2519.360000 ;
        RECT 0.000000 2552.720000 2568.640000 2560.880000 ;
        RECT 109.300000 1622.300000 813.600000 1624.100000 ;
        RECT 109.300000 1663.600000 813.600000 1665.400000 ;
        RECT 4.500000 1645.600000 1026.100000 1648.960000 ;
        RECT 4.500000 1319.200000 111.100000 1322.560000 ;
        RECT 4.500000 1373.600000 111.100000 1376.960000 ;
        RECT 4.500000 1428.000000 111.100000 1431.360000 ;
        RECT 4.500000 1482.400000 111.100000 1485.760000 ;
        RECT 4.500000 1536.800000 111.100000 1540.160000 ;
        RECT 4.500000 1591.200000 111.100000 1594.560000 ;
        RECT 4.500000 1700.000000 111.100000 1703.360000 ;
        RECT 4.500000 1754.400000 111.100000 1757.760000 ;
        RECT 4.500000 1808.800000 111.100000 1812.160000 ;
        RECT 4.500000 1863.200000 111.100000 1866.560000 ;
        RECT 4.500000 1917.600000 111.100000 1920.960000 ;
        RECT 811.800000 1700.000000 1026.100000 1703.360000 ;
        RECT 811.800000 1754.400000 1026.100000 1757.760000 ;
        RECT 811.800000 1808.800000 1026.100000 1812.160000 ;
        RECT 811.800000 1863.200000 1026.100000 1866.560000 ;
        RECT 811.800000 1917.600000 1026.100000 1920.960000 ;
        RECT 800.570000 1610.400000 813.600000 1612.140000 ;
        RECT 109.300000 2342.300000 813.600000 2344.100000 ;
        RECT 4.500000 2244.000000 111.100000 2247.360000 ;
        RECT 4.500000 1972.000000 111.100000 1975.360000 ;
        RECT 4.500000 2026.400000 111.100000 2029.760000 ;
        RECT 4.500000 2080.800000 111.100000 2084.160000 ;
        RECT 4.500000 2135.200000 111.100000 2138.560000 ;
        RECT 4.500000 2189.600000 111.100000 2192.960000 ;
        RECT 4.500000 2298.400000 111.100000 2301.760000 ;
        RECT 109.300000 2330.400000 122.330000 2332.140000 ;
        RECT 811.800000 2244.000000 1026.100000 2247.360000 ;
        RECT 811.800000 1972.000000 1026.100000 1975.360000 ;
        RECT 811.800000 2026.400000 1026.100000 2029.760000 ;
        RECT 811.800000 2080.800000 1026.100000 2084.160000 ;
        RECT 811.800000 2135.200000 1026.100000 2138.560000 ;
        RECT 811.800000 2189.600000 1026.100000 2192.960000 ;
        RECT 811.800000 2298.400000 1026.100000 2301.760000 ;
        RECT 1753.300000 1576.200000 2457.600000 1578.000000 ;
        RECT 1784.300000 1631.500000 2464.800000 1633.300000 ;
        RECT 1703.000000 1645.600000 1786.100000 1648.960000 ;
        RECT 1703.000000 1700.000000 1786.100000 1703.360000 ;
        RECT 1703.000000 1754.400000 1786.100000 1757.760000 ;
        RECT 1703.000000 1808.800000 1786.100000 1812.160000 ;
        RECT 1703.000000 1863.200000 1786.100000 1866.560000 ;
        RECT 1703.000000 1917.600000 1786.100000 1920.960000 ;
        RECT 2455.800000 1319.200000 2564.140000 1322.560000 ;
        RECT 2455.800000 1373.600000 2564.140000 1376.960000 ;
        RECT 2455.800000 1428.000000 2564.140000 1431.360000 ;
        RECT 2455.800000 1482.400000 2564.140000 1485.760000 ;
        RECT 2455.800000 1536.800000 2564.140000 1540.160000 ;
        RECT 2463.000000 1645.600000 2564.140000 1648.960000 ;
        RECT 2463.000000 1700.000000 2564.140000 1703.360000 ;
        RECT 2463.000000 1754.400000 2564.140000 1757.760000 ;
        RECT 2463.000000 1808.800000 2564.140000 1812.160000 ;
        RECT 2463.000000 1863.200000 2564.140000 1866.560000 ;
        RECT 2463.000000 1917.600000 2564.140000 1920.960000 ;
        RECT 1784.300000 2334.000000 2464.800000 2335.800000 ;
        RECT 1703.000000 2244.000000 1786.100000 2247.360000 ;
        RECT 1703.000000 1972.000000 1786.100000 1975.360000 ;
        RECT 1703.000000 2026.400000 1786.100000 2029.760000 ;
        RECT 1703.000000 2080.800000 1786.100000 2084.160000 ;
        RECT 1703.000000 2135.200000 1786.100000 2138.560000 ;
        RECT 1703.000000 2189.600000 1786.100000 2192.960000 ;
        RECT 1703.000000 2298.400000 1786.100000 2301.760000 ;
        RECT 1691.970000 2322.100000 1704.800000 2323.840000 ;
        RECT 2463.000000 2244.000000 2564.140000 2247.360000 ;
        RECT 2463.000000 1972.000000 2564.140000 1975.360000 ;
        RECT 2463.000000 2026.400000 2564.140000 2029.760000 ;
        RECT 2463.000000 2080.800000 2564.140000 2084.160000 ;
        RECT 2463.000000 2135.200000 2564.140000 2138.560000 ;
        RECT 2463.000000 2189.600000 2564.140000 2192.960000 ;
        RECT 2463.000000 2298.400000 2564.140000 2301.760000 ;
        RECT 2451.970000 2322.100000 2464.800000 2323.840000 ;
        RECT 788.000000 880.000000 792.160000 881.800000 ;
        RECT 776.100000 868.100000 777.840000 869.840000 ;
        RECT 861.260000 868.100000 863.000000 869.840000 ;
        RECT 2443.900000 195.330000 2445.640000 197.630000 ;
        RECT 2455.800000 195.365000 2457.600000 197.595000 ;
        RECT 2443.900000 909.460000 2445.640000 911.200000 ;
        RECT 799.900000 1610.400000 801.640000 1612.140000 ;
        RECT 121.260000 2330.400000 123.000000 2332.140000 ;
        RECT 1691.100000 2322.100000 1692.840000 2323.840000 ;
        RECT 2451.100000 2322.100000 2452.840000 2323.840000 ;
    END
# end of P/G power stripe data as pin

  END VSS
  PIN VDD
    DIRECTION INOUT ;
    USE POWER ;
    PORT
      LAYER met4 ;
        RECT 2543.740000 2556.800000 2551.900000 2564.960000 ;
    END
    PORT
      LAYER met4 ;
        RECT 2543.740000 0.000000 2551.900000 8.160000 ;
    END
    PORT
      LAYER met4 ;
        RECT 16.740000 2556.800000 24.900000 2564.960000 ;
    END
    PORT
      LAYER met4 ;
        RECT 16.740000 0.000000 24.900000 8.160000 ;
    END
    PORT
      LAYER met5 ;
        RECT 2560.480000 2540.480000 2568.640000 2548.640000 ;
    END
    PORT
      LAYER met5 ;
        RECT 0.000000 2540.480000 8.160000 2548.640000 ;
    END
    PORT
      LAYER met5 ;
        RECT 2560.480000 16.320000 2568.640000 24.480000 ;
    END
    PORT
      LAYER met5 ;
        RECT 0.000000 16.320000 8.160000 24.480000 ;
    END

# P/G power stripe data as pin
    PORT
      LAYER met4 ;
        RECT 16.740000 0.000000 24.900000 2564.960000 ;
        RECT 40.800000 16.320000 44.160000 2548.640000 ;
        RECT 95.200000 16.320000 98.560000 2548.640000 ;
        RECT 112.900000 947.200000 114.700000 1620.500000 ;
        RECT 808.200000 947.200000 810.000000 1620.500000 ;
        RECT 911.200000 876.400000 914.560000 2548.640000 ;
        RECT 856.800000 876.400000 860.160000 2548.640000 ;
        RECT 1074.400000 876.400000 1077.760000 1636.900000 ;
        RECT 965.600000 876.400000 968.960000 2548.640000 ;
        RECT 1020.000000 876.400000 1023.360000 2548.640000 ;
        RECT 1128.800000 876.400000 1132.160000 1636.900000 ;
        RECT 1183.200000 876.400000 1186.560000 1636.900000 ;
        RECT 1237.600000 876.400000 1240.960000 1636.900000 ;
        RECT 1564.000000 16.320000 1567.360000 1636.900000 ;
        RECT 1509.600000 876.400000 1512.960000 1636.900000 ;
        RECT 1455.200000 876.400000 1458.560000 1636.900000 ;
        RECT 1400.800000 876.400000 1404.160000 1636.900000 ;
        RECT 1346.400000 876.400000 1349.760000 1636.900000 ;
        RECT 1292.000000 876.400000 1295.360000 1636.900000 ;
        RECT 1756.900000 901.100000 1758.700000 1574.400000 ;
        RECT 1727.200000 16.320000 1730.560000 2548.640000 ;
        RECT 1672.800000 16.320000 1676.160000 1636.900000 ;
        RECT 1618.400000 16.320000 1621.760000 1636.900000 ;
        RECT 2543.740000 0.000000 2551.900000 2564.960000 ;
        RECT 2488.800000 16.320000 2492.160000 2548.640000 ;
        RECT 2452.200000 901.100000 2454.000000 1574.400000 ;
        RECT 852.900000 181.100000 854.700000 878.200000 ;
        RECT 784.400000 181.100000 786.200000 878.200000 ;
        RECT 112.900000 181.100000 114.700000 878.200000 ;
        RECT 802.400000 16.320000 805.760000 949.000000 ;
        RECT 639.200000 16.320000 642.560000 182.900000 ;
        RECT 312.800000 16.320000 316.160000 182.900000 ;
        RECT 258.400000 16.320000 261.760000 182.900000 ;
        RECT 204.000000 16.320000 207.360000 182.900000 ;
        RECT 149.600000 16.320000 152.960000 182.900000 ;
        RECT 584.800000 16.320000 588.160000 182.900000 ;
        RECT 530.400000 16.320000 533.760000 182.900000 ;
        RECT 476.000000 16.320000 479.360000 182.900000 ;
        RECT 421.600000 16.320000 424.960000 182.900000 ;
        RECT 367.200000 16.320000 370.560000 182.900000 ;
        RECT 911.200000 16.320000 914.560000 182.900000 ;
        RECT 856.800000 16.320000 860.160000 182.900000 ;
        RECT 748.000000 16.320000 751.360000 182.900000 ;
        RECT 693.600000 16.320000 696.960000 182.900000 ;
        RECT 1237.600000 16.320000 1240.960000 182.900000 ;
        RECT 1183.200000 16.320000 1186.560000 182.900000 ;
        RECT 1128.800000 16.320000 1132.160000 182.900000 ;
        RECT 1074.400000 16.320000 1077.760000 182.900000 ;
        RECT 1020.000000 16.320000 1023.360000 182.900000 ;
        RECT 965.600000 16.320000 968.960000 182.900000 ;
        RECT 639.200000 876.400000 642.560000 949.000000 ;
        RECT 149.600000 876.400000 152.960000 949.000000 ;
        RECT 312.800000 876.400000 316.160000 949.000000 ;
        RECT 258.400000 876.400000 261.760000 949.000000 ;
        RECT 204.000000 876.400000 207.360000 949.000000 ;
        RECT 476.000000 876.400000 479.360000 949.000000 ;
        RECT 421.600000 876.400000 424.960000 949.000000 ;
        RECT 367.200000 876.400000 370.560000 949.000000 ;
        RECT 584.800000 876.400000 588.160000 949.000000 ;
        RECT 530.400000 876.400000 533.760000 949.000000 ;
        RECT 748.000000 876.400000 751.360000 949.000000 ;
        RECT 693.600000 876.400000 696.960000 949.000000 ;
        RECT 1524.400000 181.100000 1526.200000 878.200000 ;
        RECT 2452.200000 181.100000 2454.000000 854.400000 ;
        RECT 1756.900000 181.100000 1758.700000 854.400000 ;
        RECT 1509.600000 16.320000 1512.960000 182.900000 ;
        RECT 1455.200000 16.320000 1458.560000 182.900000 ;
        RECT 1400.800000 16.320000 1404.160000 182.900000 ;
        RECT 1346.400000 16.320000 1349.760000 182.900000 ;
        RECT 1292.000000 16.320000 1295.360000 182.900000 ;
        RECT 1890.400000 16.320000 1893.760000 182.900000 ;
        RECT 1836.000000 16.320000 1839.360000 182.900000 ;
        RECT 1781.600000 16.320000 1784.960000 182.900000 ;
        RECT 2216.800000 16.320000 2220.160000 182.900000 ;
        RECT 2162.400000 16.320000 2165.760000 182.900000 ;
        RECT 2108.000000 16.320000 2111.360000 182.900000 ;
        RECT 2053.600000 16.320000 2056.960000 182.900000 ;
        RECT 1999.200000 16.320000 2002.560000 182.900000 ;
        RECT 1944.800000 16.320000 1948.160000 182.900000 ;
        RECT 2434.400000 16.320000 2437.760000 182.900000 ;
        RECT 2380.000000 16.320000 2383.360000 182.900000 ;
        RECT 2325.600000 16.320000 2328.960000 182.900000 ;
        RECT 2271.200000 16.320000 2274.560000 182.900000 ;
        RECT 1890.400000 852.600000 1893.760000 902.900000 ;
        RECT 1836.000000 852.600000 1839.360000 902.900000 ;
        RECT 1781.600000 852.600000 1784.960000 902.900000 ;
        RECT 2053.600000 852.600000 2056.960000 902.900000 ;
        RECT 1999.200000 852.600000 2002.560000 902.900000 ;
        RECT 1944.800000 852.600000 1948.160000 902.900000 ;
        RECT 2216.800000 852.600000 2220.160000 902.900000 ;
        RECT 2162.400000 852.600000 2165.760000 902.900000 ;
        RECT 2108.000000 852.600000 2111.360000 902.900000 ;
        RECT 2380.000000 852.600000 2383.360000 902.900000 ;
        RECT 2325.600000 852.600000 2328.960000 902.900000 ;
        RECT 2271.200000 852.600000 2274.560000 902.900000 ;
        RECT 2434.400000 852.600000 2437.760000 902.900000 ;
        RECT 1027.900000 1635.100000 1029.700000 2332.200000 ;
        RECT 808.200000 1667.200000 810.000000 2340.500000 ;
        RECT 112.900000 1667.200000 114.700000 2340.500000 ;
        RECT 639.200000 1618.700000 642.560000 1669.000000 ;
        RECT 149.600000 1618.700000 152.960000 1669.000000 ;
        RECT 204.000000 1618.700000 207.360000 1669.000000 ;
        RECT 312.800000 1618.700000 316.160000 1669.000000 ;
        RECT 258.400000 1618.700000 261.760000 1669.000000 ;
        RECT 367.200000 1618.700000 370.560000 1669.000000 ;
        RECT 476.000000 1618.700000 479.360000 1669.000000 ;
        RECT 421.600000 1618.700000 424.960000 1669.000000 ;
        RECT 530.400000 1618.700000 533.760000 1669.000000 ;
        RECT 584.800000 1618.700000 588.160000 1669.000000 ;
        RECT 802.400000 1618.700000 805.760000 1669.000000 ;
        RECT 693.600000 1618.700000 696.960000 1669.000000 ;
        RECT 748.000000 1618.700000 751.360000 1669.000000 ;
        RECT 639.200000 2338.700000 642.560000 2548.640000 ;
        RECT 312.800000 2338.700000 316.160000 2548.640000 ;
        RECT 258.400000 2338.700000 261.760000 2548.640000 ;
        RECT 204.000000 2338.700000 207.360000 2548.640000 ;
        RECT 149.600000 2338.700000 152.960000 2548.640000 ;
        RECT 584.800000 2338.700000 588.160000 2548.640000 ;
        RECT 530.400000 2338.700000 533.760000 2548.640000 ;
        RECT 476.000000 2338.700000 479.360000 2548.640000 ;
        RECT 421.600000 2338.700000 424.960000 2548.640000 ;
        RECT 367.200000 2338.700000 370.560000 2548.640000 ;
        RECT 802.400000 2338.700000 805.760000 2548.640000 ;
        RECT 748.000000 2338.700000 751.360000 2548.640000 ;
        RECT 693.600000 2338.700000 696.960000 2548.640000 ;
        RECT 1237.600000 2330.400000 1240.960000 2548.640000 ;
        RECT 1183.200000 2330.400000 1186.560000 2548.640000 ;
        RECT 1128.800000 2330.400000 1132.160000 2548.640000 ;
        RECT 1074.400000 2330.400000 1077.760000 2548.640000 ;
        RECT 2459.400000 1635.100000 2461.200000 2332.200000 ;
        RECT 1787.900000 1635.100000 1789.700000 2332.200000 ;
        RECT 1699.400000 1635.100000 1701.200000 2332.200000 ;
        RECT 1781.600000 1572.600000 1784.960000 1608.170000 ;
        RECT 1836.000000 1572.600000 1839.360000 1636.900000 ;
        RECT 1890.400000 1572.600000 1893.760000 1636.900000 ;
        RECT 2053.600000 1572.600000 2056.960000 1636.900000 ;
        RECT 1999.200000 1572.600000 2002.560000 1636.900000 ;
        RECT 1944.800000 1572.600000 1948.160000 1636.900000 ;
        RECT 2216.800000 1572.600000 2220.160000 1636.900000 ;
        RECT 2162.400000 1572.600000 2165.760000 1636.900000 ;
        RECT 2108.000000 1572.600000 2111.360000 1636.900000 ;
        RECT 2271.200000 1572.600000 2274.560000 1636.900000 ;
        RECT 2325.600000 1572.600000 2328.960000 1636.900000 ;
        RECT 2380.000000 1572.600000 2383.360000 1636.900000 ;
        RECT 2434.400000 1572.600000 2437.760000 1636.900000 ;
        RECT 1564.000000 2330.400000 1567.360000 2548.640000 ;
        RECT 1509.600000 2330.400000 1512.960000 2548.640000 ;
        RECT 1455.200000 2330.400000 1458.560000 2548.640000 ;
        RECT 1400.800000 2330.400000 1404.160000 2548.640000 ;
        RECT 1346.400000 2330.400000 1349.760000 2548.640000 ;
        RECT 1292.000000 2330.400000 1295.360000 2548.640000 ;
        RECT 1890.400000 2330.400000 1893.760000 2548.640000 ;
        RECT 1836.000000 2330.400000 1839.360000 2548.640000 ;
        RECT 1672.800000 2330.400000 1676.160000 2548.640000 ;
        RECT 1618.400000 2330.400000 1621.760000 2548.640000 ;
        RECT 1781.600000 2366.405000 1784.960000 2548.640000 ;
        RECT 2216.800000 2330.400000 2220.160000 2548.640000 ;
        RECT 2162.400000 2330.400000 2165.760000 2548.640000 ;
        RECT 2108.000000 2330.400000 2111.360000 2548.640000 ;
        RECT 2053.600000 2330.400000 2056.960000 2548.640000 ;
        RECT 1999.200000 2330.400000 2002.560000 2548.640000 ;
        RECT 1944.800000 2330.400000 1948.160000 2548.640000 ;
        RECT 2434.400000 2330.400000 2437.760000 2548.640000 ;
        RECT 2380.000000 2330.400000 2383.360000 2548.640000 ;
        RECT 2325.600000 2330.400000 2328.960000 2548.640000 ;
        RECT 2271.200000 2330.400000 2274.560000 2548.640000 ;
        RECT 117.860000 871.500000 119.600000 873.240000 ;
        RECT 1519.500000 186.060000 1521.240000 187.800000 ;
        RECT 2447.300000 186.060000 2449.040000 187.800000 ;
        RECT 1761.860000 906.060000 1763.600000 907.800000 ;
        RECT 803.300000 1613.800000 805.040000 1615.540000 ;
        RECT 1032.860000 1640.060000 1034.600000 1641.800000 ;
        RECT 803.300000 2333.800000 805.040000 2335.540000 ;
        RECT 1781.600000 2366.400000 1784.960000 2369.760000 ;
        RECT 2454.500000 2325.500000 2456.240000 2327.240000 ;
      LAYER met5 ;
        RECT 0.000000 16.320000 2568.640000 24.480000 ;
        RECT 16.740000 27.200000 2551.900000 30.560000 ;
        RECT 16.740000 81.600000 2551.900000 84.960000 ;
        RECT 16.740000 136.000000 2551.900000 139.360000 ;
        RECT 852.900000 181.100000 1526.200000 182.900000 ;
        RECT 852.900000 876.400000 1526.200000 878.200000 ;
        RECT 16.740000 897.600000 1730.575000 900.960000 ;
        RECT 808.200000 952.000000 1758.700000 955.360000 ;
        RECT 808.200000 1006.400000 1758.700000 1009.760000 ;
        RECT 808.200000 1060.800000 1758.700000 1064.160000 ;
        RECT 808.200000 1115.200000 1758.700000 1118.560000 ;
        RECT 808.200000 1169.600000 1758.700000 1172.960000 ;
        RECT 808.200000 1224.000000 1758.700000 1227.360000 ;
        RECT 808.200000 1278.400000 1758.700000 1281.760000 ;
        RECT 112.900000 181.100000 786.200000 182.900000 ;
        RECT 16.740000 190.400000 114.700000 193.760000 ;
        RECT 16.740000 244.800000 114.700000 248.160000 ;
        RECT 16.740000 299.200000 114.700000 302.560000 ;
        RECT 16.740000 353.600000 114.700000 356.960000 ;
        RECT 16.740000 408.000000 114.700000 411.360000 ;
        RECT 16.740000 462.400000 114.700000 465.760000 ;
        RECT 16.740000 516.800000 114.700000 520.160000 ;
        RECT 16.740000 571.200000 114.700000 574.560000 ;
        RECT 16.740000 625.600000 114.700000 628.960000 ;
        RECT 784.400000 190.400000 854.700000 193.760000 ;
        RECT 784.400000 244.800000 854.700000 248.160000 ;
        RECT 784.400000 299.200000 854.700000 302.560000 ;
        RECT 784.400000 353.600000 854.700000 356.960000 ;
        RECT 784.400000 408.000000 854.700000 411.360000 ;
        RECT 784.400000 462.400000 854.700000 465.760000 ;
        RECT 784.400000 516.800000 854.700000 520.160000 ;
        RECT 784.400000 571.200000 854.700000 574.560000 ;
        RECT 784.400000 625.600000 854.700000 628.960000 ;
        RECT 112.900000 876.400000 786.200000 878.200000 ;
        RECT 112.900000 947.200000 810.000000 949.000000 ;
        RECT 16.740000 680.000000 114.700000 683.360000 ;
        RECT 16.740000 734.400000 114.700000 737.760000 ;
        RECT 16.740000 788.800000 114.700000 792.160000 ;
        RECT 16.740000 843.200000 114.700000 846.560000 ;
        RECT 112.900000 871.500000 118.730000 873.240000 ;
        RECT 16.740000 952.000000 114.700000 955.360000 ;
        RECT 16.740000 1006.400000 114.700000 1009.760000 ;
        RECT 16.740000 1060.800000 114.700000 1064.160000 ;
        RECT 16.740000 1115.200000 114.700000 1118.560000 ;
        RECT 16.740000 1169.600000 114.700000 1172.960000 ;
        RECT 16.740000 1224.000000 114.700000 1227.360000 ;
        RECT 16.740000 1278.400000 114.700000 1281.760000 ;
        RECT 784.400000 680.000000 854.700000 683.360000 ;
        RECT 784.400000 734.400000 854.700000 737.760000 ;
        RECT 784.400000 788.800000 854.700000 792.160000 ;
        RECT 784.400000 843.200000 854.700000 846.560000 ;
        RECT 1756.900000 181.100000 2454.000000 182.900000 ;
        RECT 1524.400000 190.400000 1758.700000 193.760000 ;
        RECT 1524.400000 244.800000 1758.700000 248.160000 ;
        RECT 1524.400000 299.200000 1758.700000 302.560000 ;
        RECT 1520.370000 186.060000 1526.200000 187.800000 ;
        RECT 1524.400000 353.600000 1758.700000 356.960000 ;
        RECT 1524.400000 408.000000 1758.700000 411.360000 ;
        RECT 1524.400000 462.400000 1758.700000 465.760000 ;
        RECT 1524.400000 516.800000 1758.700000 520.160000 ;
        RECT 1524.400000 571.200000 1758.700000 574.560000 ;
        RECT 1524.400000 625.600000 1758.700000 628.960000 ;
        RECT 2452.200000 190.400000 2551.900000 193.760000 ;
        RECT 2447.970000 186.060000 2454.000000 187.800000 ;
        RECT 2452.200000 244.800000 2551.900000 248.160000 ;
        RECT 2452.200000 299.200000 2551.900000 302.560000 ;
        RECT 2452.200000 353.600000 2551.900000 356.960000 ;
        RECT 2452.200000 408.000000 2551.900000 411.360000 ;
        RECT 2452.200000 462.400000 2551.900000 465.760000 ;
        RECT 2452.200000 516.800000 2551.900000 520.160000 ;
        RECT 2452.200000 571.200000 2551.900000 574.560000 ;
        RECT 2452.200000 625.600000 2551.900000 628.960000 ;
        RECT 1756.900000 901.100000 2454.000000 902.900000 ;
        RECT 1756.900000 852.600000 2454.000000 854.400000 ;
        RECT 1524.400000 680.000000 1758.700000 683.360000 ;
        RECT 1524.400000 734.400000 1758.700000 737.760000 ;
        RECT 1524.400000 788.800000 1758.700000 792.160000 ;
        RECT 1524.400000 843.200000 1758.700000 846.560000 ;
        RECT 1756.900000 906.060000 1762.930000 907.800000 ;
        RECT 2452.200000 680.000000 2551.900000 683.360000 ;
        RECT 2452.200000 734.400000 2551.900000 737.760000 ;
        RECT 2452.200000 788.800000 2551.900000 792.160000 ;
        RECT 2452.200000 843.200000 2551.900000 846.560000 ;
        RECT 2452.200000 952.000000 2551.900000 955.360000 ;
        RECT 2488.810000 897.600000 2551.900000 900.960000 ;
        RECT 2452.200000 1006.400000 2551.900000 1009.760000 ;
        RECT 2452.200000 1060.800000 2551.900000 1064.160000 ;
        RECT 2452.200000 1115.200000 2551.900000 1118.560000 ;
        RECT 2452.200000 1169.600000 2551.900000 1172.960000 ;
        RECT 2452.200000 1224.000000 2551.900000 1227.360000 ;
        RECT 2452.200000 1278.400000 2551.900000 1281.760000 ;
        RECT 808.200000 1441.600000 1758.700000 1444.960000 ;
        RECT 808.200000 1332.800000 1758.700000 1336.160000 ;
        RECT 808.200000 1387.200000 1758.700000 1390.560000 ;
        RECT 808.200000 1496.000000 1758.700000 1499.360000 ;
        RECT 808.200000 1550.400000 1758.700000 1553.760000 ;
        RECT 1027.900000 1635.100000 1701.200000 1636.900000 ;
        RECT 808.200000 1604.800000 2551.900000 1608.160000 ;
        RECT 1027.900000 2330.400000 1701.200000 2332.200000 ;
        RECT 16.740000 2366.400000 2551.900000 2369.760000 ;
        RECT 16.740000 2420.800000 2551.900000 2424.160000 ;
        RECT 16.740000 2475.200000 2551.900000 2478.560000 ;
        RECT 16.740000 2529.600000 2551.900000 2532.960000 ;
        RECT 0.000000 2540.480000 2568.640000 2548.640000 ;
        RECT 112.900000 1618.700000 810.000000 1620.500000 ;
        RECT 112.900000 1667.200000 810.000000 1669.000000 ;
        RECT 16.740000 1441.600000 114.700000 1444.960000 ;
        RECT 16.740000 1332.800000 114.700000 1336.160000 ;
        RECT 16.740000 1387.200000 114.700000 1390.560000 ;
        RECT 16.740000 1496.000000 114.700000 1499.360000 ;
        RECT 16.740000 1550.400000 114.700000 1553.760000 ;
        RECT 16.740000 1604.800000 114.700000 1608.160000 ;
        RECT 16.740000 1659.200000 98.550000 1662.560000 ;
        RECT 16.740000 1713.600000 114.700000 1716.960000 ;
        RECT 16.740000 1768.000000 114.700000 1771.360000 ;
        RECT 16.740000 1822.400000 114.700000 1825.760000 ;
        RECT 16.740000 1876.800000 114.700000 1880.160000 ;
        RECT 856.775000 1659.200000 1029.700000 1662.560000 ;
        RECT 808.200000 1713.600000 1029.700000 1716.960000 ;
        RECT 808.200000 1768.000000 1029.700000 1771.360000 ;
        RECT 808.200000 1822.400000 1029.700000 1825.760000 ;
        RECT 808.200000 1876.800000 1029.700000 1880.160000 ;
        RECT 803.300000 1614.670000 805.040000 1619.830000 ;
        RECT 1027.900000 1640.060000 1033.730000 1641.800000 ;
        RECT 112.900000 2338.700000 810.000000 2340.500000 ;
        RECT 16.740000 1931.200000 114.700000 1934.560000 ;
        RECT 16.740000 1985.600000 114.700000 1988.960000 ;
        RECT 16.740000 2040.000000 114.700000 2043.360000 ;
        RECT 16.740000 2094.400000 114.700000 2097.760000 ;
        RECT 16.740000 2148.800000 114.700000 2152.160000 ;
        RECT 16.740000 2203.200000 114.700000 2206.560000 ;
        RECT 16.740000 2257.600000 114.700000 2260.960000 ;
        RECT 16.740000 2312.000000 114.700000 2315.360000 ;
        RECT 808.200000 1931.200000 1029.700000 1934.560000 ;
        RECT 808.200000 1985.600000 1029.700000 1988.960000 ;
        RECT 808.200000 2040.000000 1029.700000 2043.360000 ;
        RECT 808.200000 2094.400000 1029.700000 2097.760000 ;
        RECT 808.200000 2148.800000 1029.700000 2152.160000 ;
        RECT 808.200000 2203.200000 1029.700000 2206.560000 ;
        RECT 808.200000 2257.600000 1029.700000 2260.960000 ;
        RECT 808.200000 2312.000000 1029.700000 2315.360000 ;
        RECT 803.300000 2334.670000 805.040000 2339.830000 ;
        RECT 1756.900000 1572.600000 2454.000000 1574.400000 ;
        RECT 1787.900000 1635.100000 2461.200000 1636.900000 ;
        RECT 1699.400000 1659.200000 1789.700000 1662.560000 ;
        RECT 1699.400000 1713.600000 1789.700000 1716.960000 ;
        RECT 1699.400000 1768.000000 1789.700000 1771.360000 ;
        RECT 1699.400000 1822.400000 1789.700000 1825.760000 ;
        RECT 1699.400000 1876.800000 1789.700000 1880.160000 ;
        RECT 2452.200000 1441.600000 2551.900000 1444.960000 ;
        RECT 2452.200000 1332.800000 2551.900000 1336.160000 ;
        RECT 2452.200000 1387.200000 2551.900000 1390.560000 ;
        RECT 2452.200000 1496.000000 2551.900000 1499.360000 ;
        RECT 2452.200000 1550.400000 2551.900000 1553.760000 ;
        RECT 2459.400000 1659.200000 2551.900000 1662.560000 ;
        RECT 2459.400000 1713.600000 2551.900000 1716.960000 ;
        RECT 2459.400000 1768.000000 2551.900000 1771.360000 ;
        RECT 2459.400000 1822.400000 2551.900000 1825.760000 ;
        RECT 2459.400000 1876.800000 2551.900000 1880.160000 ;
        RECT 1787.900000 2330.400000 2461.200000 2332.200000 ;
        RECT 1699.400000 1931.200000 1789.700000 1934.560000 ;
        RECT 1699.400000 1985.600000 1789.700000 1988.960000 ;
        RECT 1699.400000 2040.000000 1789.700000 2043.360000 ;
        RECT 1699.400000 2094.400000 1789.700000 2097.760000 ;
        RECT 1699.400000 2148.800000 1789.700000 2152.160000 ;
        RECT 1699.400000 2203.200000 1789.700000 2206.560000 ;
        RECT 1699.400000 2257.600000 1789.700000 2260.960000 ;
        RECT 1699.400000 2312.000000 1789.700000 2315.360000 ;
        RECT 2459.400000 1931.200000 2551.900000 1934.560000 ;
        RECT 2459.400000 1985.600000 2551.900000 1988.960000 ;
        RECT 2459.400000 2040.000000 2551.900000 2043.360000 ;
        RECT 2459.400000 2094.400000 2551.900000 2097.760000 ;
        RECT 2459.400000 2148.800000 2551.900000 2152.160000 ;
        RECT 2459.400000 2203.200000 2551.900000 2206.560000 ;
        RECT 2455.370000 2325.500000 2461.200000 2327.240000 ;
        RECT 2459.400000 2257.600000 2551.900000 2260.960000 ;
        RECT 2459.400000 2312.000000 2551.900000 2315.360000 ;
        RECT 117.860000 871.500000 119.600000 873.240000 ;
        RECT 1519.500000 186.060000 1521.240000 187.800000 ;
        RECT 2447.300000 186.060000 2449.040000 187.800000 ;
        RECT 1761.860000 906.060000 1763.600000 907.800000 ;
        RECT 2488.800000 897.600000 2492.160000 900.960000 ;
        RECT 95.200000 1659.200000 98.560000 1662.560000 ;
        RECT 803.300000 1613.800000 805.040000 1615.540000 ;
        RECT 1032.860000 1640.060000 1034.600000 1641.800000 ;
        RECT 803.300000 2333.800000 805.040000 2335.540000 ;
        RECT 2454.500000 2325.500000 2456.240000 2327.240000 ;
    END
# end of P/G power stripe data as pin

  END VDD
  OBS
    LAYER li1 ;
      RECT 0.000000 0.000000 2568.640000 2564.960000 ;
    LAYER met1 ;
      RECT 0.000000 0.000000 2568.640000 2564.960000 ;
    LAYER met2 ;
      RECT 0.000000 0.000000 2568.640000 2564.960000 ;
    LAYER met3 ;
      RECT 0.000000 0.000000 2568.640000 2564.960000 ;
    LAYER met4 ;
      RECT 0.000000 0.000000 2568.640000 2564.960000 ;
    LAYER met5 ;
      RECT 0.000000 0.000000 2568.640000 2564.960000 ;
  END
END deconv_kernel_estimator_top_level

END LIBRARY
